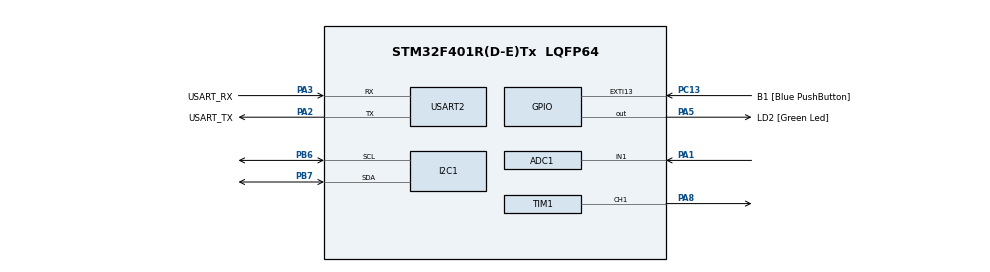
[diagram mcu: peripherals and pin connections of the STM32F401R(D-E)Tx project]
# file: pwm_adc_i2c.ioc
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ADC1.Channel-1\#ChannelRegularConversion=ADC_CHANNEL_1
ADC1.NbrOfConversionFlag=1
ADC1.Rank-1\#ChannelRegularConversion=1
ADC1.SamplingTime-1\#ChannelRegularConversion=ADC_SAMPLETIME_3CYCLES
ADC1.master=1
Mcu.Family=STM32F4
Mcu.Name=STM32F401R(D-E)Tx
Mcu.Package=LQFP64
NVIC.PriorityGroup=NVIC_PRIORITYGROUP_0
PA1.Signal=ADCx_IN1
PA13.GPIO_Label=TMS
PA13.Mode=Serial_Wire
PA13.Signal=SYS_JTMS-SWDIO
PA14.GPIO_Label=TCK
PA14.Mode=Serial_Wire
PA14.Signal=SYS_JTCK-SWCLK
PA2.GPIO_Label=USART_TX
PA2.GPIO_Mode=GPIO_MODE_AF_PP
PA2.GPIO_PuPd=GPIO_NOPULL
PA2.GPIO_Speed=GPIO_SPEED_FREQ_LOW
PA2.Mode=Asynchronous
PA2.Signal=USART2_TX
PA3.GPIO_Label=USART_RX
PA3.GPIO_Mode=GPIO_MODE_AF_PP
PA3.GPIO_PuPd=GPIO_NOPULL
PA3.GPIO_Speed=GPIO_SPEED_FREQ_LOW
PA3.Mode=Asynchronous
PA3.Signal=USART2_RX
PA5.GPIO_Label=LD2 [Green Led]
PA5.GPIO_Mode=GPIO_MODE_OUTPUT_PP
PA5.GPIO_PuPd=GPIO_NOPULL
PA5.GPIO_Speed=GPIO_SPEED_FREQ_LOW
PA5.Signal=GPIO_Output
PA8.Signal=S_TIM1_CH1
PB3.GPIO_Label=SWO
PB3.Signal=SYS_JTDO-SWO
PB6.Mode=I2C
PB6.Signal=I2C1_SCL
PB7.Mode=I2C
PB7.Signal=I2C1_SDA
PC13-ANTI_TAMP.GPIO_Label=B1 [Blue PushButton]
PC13-ANTI_TAMP.GPIO_ModeDefaultEXTI=GPIO_MODE_IT_FALLING
PC13-ANTI_TAMP.GPIO_PuPd=GPIO_NOPULL
PC13-ANTI_TAMP.Signal=GPXTI13
PC14-OSC32_IN.Mode=LSE-External-Oscillator
PC14-OSC32_IN.Signal=RCC_OSC32_IN
PC15-OSC32_OUT.Mode=LSE-External-Oscillator
PC15-OSC32_OUT.Signal=RCC_OSC32_OUT
PH0\ -\ OSC_IN.Mode=HSE-External-Clock-Source
PH0\ -\ OSC_IN.Signal=RCC_OSC_IN
PH1\ -\ OSC_OUT.Mode=HSE-External-Clock-Source
PH1\ -\ OSC_OUT.Signal=RCC_OSC_OUT
ProjectManager.HeapSize=0x200
ProjectManager.StackSize=0x400
ProjectManager.TargetToolchain=STM32CubeIDE
RCC.48MHZClocksFreq_Value=48000000
RCC.AHBFreq_Value=84000000
RCC.APB1CLKDivider=RCC_HCLK_DIV2
RCC.APB1Freq_Value=42000000
RCC.APB1TimFreq_Value=84000000
RCC.APB2Freq_Value=84000000
RCC.APB2TimFreq_Value=84000000
RCC.CortexFreq_Value=84000000
RCC.HCLKFreq_Value=84000000
RCC.HSE_VALUE=8000000
RCC.HSI_VALUE=16000000
RCC.PLLN=336
RCC.PLLP=RCC_PLLP_DIV4
RCC.PLLQ=7
RCC.SYSCLKFreq_VALUE=84000000
RCC.SYSCLKSource=RCC_SYSCLKSOURCE_PLLCLK
RCC.VCOOutputFreq_Value=336000000
SH.ADCx_IN1.0=ADC1_IN1,IN1
SH.S_TIM1_CH1.0=TIM1_CH1,PWM Generation1 CH1
TIM1.Channel-PWM\ Generation1\ CH1=TIM_CHANNEL_1
TIM1.Period=4000-1
TIM1.Pulse-PWM\ Generation1\ CH1=2000-1
USART2.VirtualMode=VM_ASYNC
VP_TIM1_VS_ClockSourceINT.Mode=Internal
board=NUCLEO-F401RE

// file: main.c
#include "main.h"

/* USER CODE BEGIN Includes */
#include "liquidcrystal_i2c.h"

/* USER CODE END Includes */

ADC_HandleTypeDef hadc1;

I2C_HandleTypeDef hi2c1;

TIM_HandleTypeDef htim1;

UART_HandleTypeDef huart2;

/* USER CODE BEGIN PV */
uint16_t AD_RES = 0;

/* USER CODE END PV */

void SystemClock_Config(void);
static void MX_GPIO_Init(void);
static void MX_USART2_UART_Init(void);
static void MX_TIM1_Init(void);
static void MX_ADC1_Init(void);
static void MX_I2C1_Init(void);

int main(void)
{

  /* MCU Configuration--------------------------------------------------------*/

  /* Reset of all peripherals, Initializes the Flash interface and the Systick. */
  HAL_Init();

  /* Configure the system clock */
  SystemClock_Config();

  /* Initialize all configured peripherals */
  MX_GPIO_Init();
  MX_USART2_UART_Init();
  MX_TIM1_Init();
  MX_ADC1_Init();
  MX_I2C1_Init();
  /* USER CODE BEGIN 2 */

  HD44780_Init(2);
  HD44780_Clear();
  HD44780_SetCursor(0,0);
  HD44780_PrintStr("HELLO");
  HAL_TIM_PWM_Start(&htim1, TIM_CHANNEL_1);
  HAL_ADC_Start_IT(&hadc1);
  /* USER CODE END 2 */

  /* Infinite loop */
  /* USER CODE BEGIN WHILE */
  while (1)
  {
    // Lire la valeur du potentiomètre
    HAL_ADC_Start(&hadc1);
    if (HAL_ADC_PollForConversion(&hadc1, HAL_MAX_DELAY) == HAL_OK)
    {
        AD_RES = HAL_ADC_GetValue(&hadc1);
    }
    HAL_ADC_Stop(&hadc1);

    // Échelonner la valeur lue pour l'adapter à la plage PWM (0-4000)
    uint16_t scaled_value = AD_RES * 4000 / 255;

    // Régler la valeur du PWM
    TIM1->CCR1 = scaled_value;

    // Attendre un court instant
    HAL_Delay(10);

      // Afficher la valeur numérique et la tension sur l'afficheur LCD
      // Convertir la valeur numérique en tension (0-3.3V)
      float voltage = (float)AD_RES * 3.3 / 4095.0;

      // Convertir la valeur numérique en chaîne de caractères
      char num_str[16];
      sprintf(num_str, "Valeur: %d", AD_RES);

      // Convertir la tension en chaîne de caractères

      // Afficher les deux valeurs sur l'écran LCD
      HD44780_Clear();
      HD44780_SetCursor(0,0);
      HD44780_PrintStr(num_str);

  }
  /* USER CODE END WHILE */

}

void SystemClock_Config(void)
{
  RCC_OscInitTypeDef RCC_OscInitStruct = {0};
  RCC_ClkInitTypeDef RCC_ClkInitStruct = {0};

  /** Configure the main internal regulator output voltage
  */
  __HAL_RCC_PWR_CLK_ENABLE();
  __HAL_PWR_VOLTAGESCALING_CONFIG(PWR_REGULATOR_VOLTAGE_SCALE2);

  /** Initializes the RCC Oscillators according to the specified parameters
  * in the RCC_OscInitTypeDef structure.
  */
  RCC_OscInitStruct.OscillatorType = RCC_OSCILLATORTYPE_HSI;
  RCC_OscInitStruct.HSIState = RCC_HSI_ON;
  RCC_OscInitStruct.HSICalibrationValue = RCC_HSICALIBRATION_DEFAULT;
  RCC_OscInitStruct.PLL.PLLState = RCC_PLL_ON;
  RCC_OscInitStruct.PLL.PLLSource = RCC_PLLSOURCE_HSI;
  RCC_OscInitStruct.PLL.PLLM = 8;
  RCC_OscInitStruct.PLL.PLLN = 80;
  RCC_OscInitStruct.PLL.PLLP = RCC_PLLP_DIV2;
  RCC_OscInitStruct.PLL.PLLQ = 7;
  if (HAL_RCC_OscConfig(&RCC_OscInitStruct) != HAL_OK)
  {
    Error_Handler();
  }

  /** Initializes the CPU, AHB and APB buses clocks
  */
  RCC_ClkInitStruct.ClockType = RCC_CLOCKTYPE_HCLK|RCC_CLOCKTYPE_SYSCLK
                              |RCC_CLOCKTYPE_PCLK1|RCC_CLOCKTYPE_PCLK2;
  RCC_ClkInitStruct.SYSCLKSource = RCC_SYSCLKSOURCE_PLLCLK;
  RCC_ClkInitStruct.AHBCLKDivider = RCC_SYSCLK_DIV1;
  RCC_ClkInitStruct.APB1CLKDivider = RCC_HCLK_DIV2;
  RCC_ClkInitStruct.APB2CLKDivider = RCC_HCLK_DIV8;

  if (HAL_RCC_ClockConfig(&RCC_ClkInitStruct, FLASH_LATENCY_2) != HAL_OK)
  {
    Error_Handler();
  }
}

static void MX_ADC1_Init(void)
{

  ADC_ChannelConfTypeDef sConfig = {0};

  /** Configure the global features of the ADC (Clock, Resolution, Data Alignment and number of conversion)
  */
  hadc1.Instance = ADC1;
  hadc1.Init.ClockPrescaler = ADC_CLOCK_SYNC_PCLK_DIV2;
  hadc1.Init.Resolution = ADC_RESOLUTION_8B;
  hadc1.Init.ScanConvMode = DISABLE;
  hadc1.Init.ContinuousConvMode = ENABLE;
  hadc1.Init.DiscontinuousConvMode = DISABLE;
  hadc1.Init.ExternalTrigConvEdge = ADC_EXTERNALTRIGCONVEDGE_NONE;
  hadc1.Init.ExternalTrigConv = ADC_SOFTWARE_START;
  hadc1.Init.DataAlign = ADC_DATAALIGN_RIGHT;
  hadc1.Init.NbrOfConversion = 1;
  hadc1.Init.DMAContinuousRequests = DISABLE;
  hadc1.Init.EOCSelection = ADC_EOC_SINGLE_CONV;
  if (HAL_ADC_Init(&hadc1) != HAL_OK)
  {
    Error_Handler();
  }

  /** Configure for the selected ADC regular channel its corresponding rank in the sequencer and its sample time.
  */
  sConfig.Channel = ADC_CHANNEL_1;
  sConfig.Rank = 1;
  sConfig.SamplingTime = ADC_SAMPLETIME_144CYCLES;
  if (HAL_ADC_ConfigChannel(&hadc1, &sConfig) != HAL_OK)
  {
    Error_Handler();
  }

}

static void MX_I2C1_Init(void)
{

  hi2c1.Instance = I2C1;
  hi2c1.Init.ClockSpeed = 100000;
  hi2c1.Init.DutyCycle = I2C_DUTYCYCLE_2;
  hi2c1.Init.OwnAddress1 = 0;
  hi2c1.Init.AddressingMode = I2C_ADDRESSINGMODE_7BIT;
  hi2c1.Init.DualAddressMode = I2C_DUALADDRESS_DISABLE;
  hi2c1.Init.OwnAddress2 = 0;
  hi2c1.Init.GeneralCallMode = I2C_GENERALCALL_DISABLE;
  hi2c1.Init.NoStretchMode = I2C_NOSTRETCH_DISABLE;
  if (HAL_I2C_Init(&hi2c1) != HAL_OK)
  {
    Error_Handler();
  }

}

static void MX_TIM1_Init(void)
{

  TIM_ClockConfigTypeDef sClockSourceConfig = {0};
  TIM_MasterConfigTypeDef sMasterConfig = {0};
  TIM_OC_InitTypeDef sConfigOC = {0};
  TIM_BreakDeadTimeConfigTypeDef sBreakDeadTimeConfig = {0};

  htim1.Instance = TIM1;
  htim1.Init.Prescaler = 0;
  htim1.Init.CounterMode = TIM_COUNTERMODE_UP;
  htim1.Init.Period = 4000-1;
  htim1.Init.ClockDivision = TIM_CLOCKDIVISION_DIV1;
  htim1.Init.RepetitionCounter = 0;
  htim1.Init.AutoReloadPreload = TIM_AUTORELOAD_PRELOAD_DISABLE;
  if (HAL_TIM_Base_Init(&htim1) != HAL_OK)
  {
    Error_Handler();
  }
  sClockSourceConfig.ClockSource = TIM_CLOCKSOURCE_INTERNAL;
  if (HAL_TIM_ConfigClockSource(&htim1, &sClockSourceConfig) != HAL_OK)
  {
    Error_Handler();
  }
  if (HAL_TIM_PWM_Init(&htim1) != HAL_OK)
  {
    Error_Handler();
  }
  sMasterConfig.MasterOutputTrigger = TIM_TRGO_RESET;
  sMasterConfig.MasterSlaveMode = TIM_MASTERSLAVEMODE_DISABLE;
  if (HAL_TIMEx_MasterConfigSynchronization(&htim1, &sMasterConfig) != HAL_OK)
  {
    Error_Handler();
  }
  sConfigOC.OCMode = TIM_OCMODE_PWM1;
  sConfigOC.Pulse = 2000-1;
  sConfigOC.OCPolarity = TIM_OCPOLARITY_HIGH;
  sConfigOC.OCNPolarity = TIM_OCNPOLARITY_HIGH;
  sConfigOC.OCFastMode = TIM_OCFAST_DISABLE;
  sConfigOC.OCIdleState = TIM_OCIDLESTATE_RESET;
  sConfigOC.OCNIdleState = TIM_OCNIDLESTATE_RESET;
  if (HAL_TIM_PWM_ConfigChannel(&htim1, &sConfigOC, TIM_CHANNEL_1) != HAL_OK)
  {
    Error_Handler();
  }
  sBreakDeadTimeConfig.OffStateRunMode = TIM_OSSR_DISABLE;
  sBreakDeadTimeConfig.OffStateIDLEMode = TIM_OSSI_DISABLE;
  sBreakDeadTimeConfig.LockLevel = TIM_LOCKLEVEL_OFF;
  sBreakDeadTimeConfig.DeadTime = 0;
  sBreakDeadTimeConfig.BreakState = TIM_BREAK_DISABLE;
  sBreakDeadTimeConfig.BreakPolarity = TIM_BREAKPOLARITY_HIGH;
  sBreakDeadTimeConfig.AutomaticOutput = TIM_AUTOMATICOUTPUT_DISABLE;
  if (HAL_TIMEx_ConfigBreakDeadTime(&htim1, &sBreakDeadTimeConfig) != HAL_OK)
  {
    Error_Handler();
  }
  HAL_TIM_MspPostInit(&htim1);

}

static void MX_USART2_UART_Init(void)
{

  huart2.Instance = USART2;
  huart2.Init.BaudRate = 115200;
  huart2.Init.WordLength = UART_WORDLENGTH_8B;
  huart2.Init.StopBits = UART_STOPBITS_1;
  huart2.Init.Parity = UART_PARITY_NONE;
  huart2.Init.Mode = UART_MODE_TX_RX;
  huart2.Init.HwFlowCtl = UART_HWCONTROL_NONE;
  huart2.Init.OverSampling = UART_OVERSAMPLING_16;
  if (HAL_UART_Init(&huart2) != HAL_OK)
  {
    Error_Handler();
  }

}

static void MX_GPIO_Init(void)
{
  GPIO_InitTypeDef GPIO_InitStruct = {0};

  /* GPIO Ports Clock Enable */
  __HAL_RCC_GPIOC_CLK_ENABLE();
  __HAL_RCC_GPIOH_CLK_ENABLE();
  __HAL_RCC_GPIOA_CLK_ENABLE();
  __HAL_RCC_GPIOB_CLK_ENABLE();

  /*Configure GPIO pin Output Level */
  HAL_GPIO_WritePin(LD2_GPIO_Port, LD2_Pin, GPIO_PIN_RESET);

  /*Configure GPIO pin : B1_Pin */
  GPIO_InitStruct.Pin = B1_Pin;
  GPIO_InitStruct.Mode = GPIO_MODE_IT_FALLING;
  GPIO_InitStruct.Pull = GPIO_NOPULL;
  HAL_GPIO_Init(B1_GPIO_Port, &GPIO_InitStruct);

  /*Configure GPIO pin : LD2_Pin */
  GPIO_InitStruct.Pin = LD2_Pin;
  GPIO_InitStruct.Mode = GPIO_MODE_OUTPUT_PP;
  GPIO_InitStruct.Pull = GPIO_NOPULL;
  GPIO_InitStruct.Speed = GPIO_SPEED_FREQ_LOW;
  HAL_GPIO_Init(LD2_GPIO_Port, &GPIO_InitStruct);

}

/* USER CODE BEGIN 4 */
void HAL_ADC_ConvCpltCallback(ADC_HandleTypeDef *hadc)
{
    // Lire la valeur du potentiomètre
    AD_RES = HAL_ADC_GetValue(hadc);

}
/* USER CODE END 4 */

void Error_Handler(void)
{
  __disable_irq();
  while (1)
  {
  }
}
